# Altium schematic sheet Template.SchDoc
size A

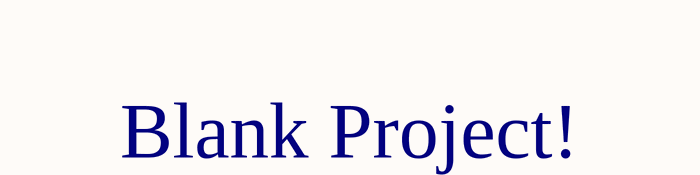
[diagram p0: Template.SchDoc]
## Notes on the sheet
- Blank Project!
